VERSION 5.8 ;
BUSBITCHARS "[]" ;
DIVIDERCHAR "/" ;
UNITS
 DATABASE MICRONS 1000 ;
END UNITS
MANUFACTURINGGRID 0.001 ;
SITE GridSite
 CLASS CORE ;
 SYMMETRY X Y ;
 SIZE 0.450 BY 0.300 ;
END GridSite
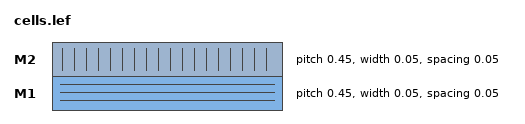
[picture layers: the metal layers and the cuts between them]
LAYER M1
 TYPE ROUTING ;
 DIRECTION HORIZONTAL ;
 PITCH 0.450 0.300 ;
 WIDTH 0.050 ;
 SPACING 0.050 ;
END M1
LAYER M2
 TYPE ROUTING ;
 DIRECTION VERTICAL ;
 PITCH 0.450 0.300 ;
 WIDTH 0.050 ;
 SPACING 0.050 ;
END M2
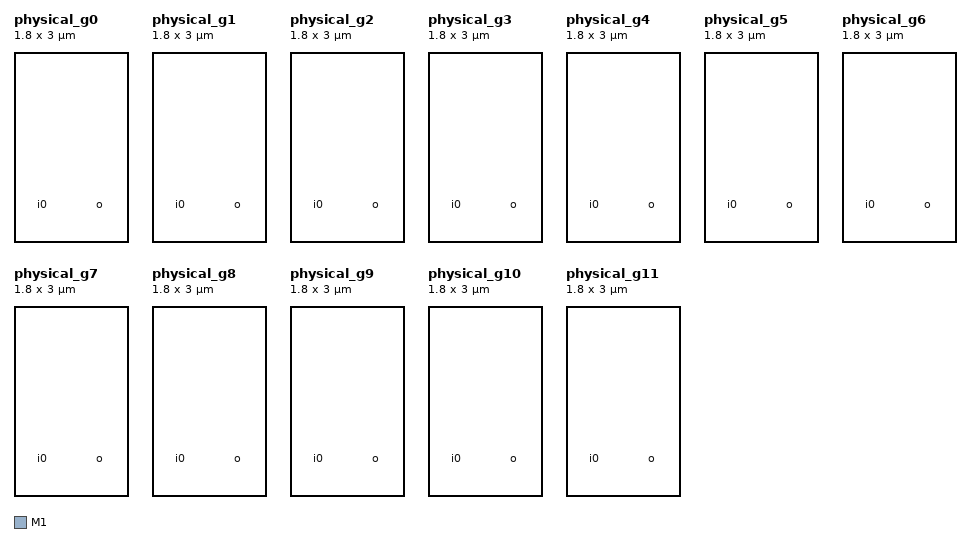
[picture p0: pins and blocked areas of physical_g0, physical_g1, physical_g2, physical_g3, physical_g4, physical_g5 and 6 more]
MACRO physical_g0
 CLASS CORE ;
 ORIGIN 0 0 ;
 SIZE 1.800000 BY 3.000000 ;
 SYMMETRY X Y ;
 SITE GridSite ;
 PIN i0
  DIRECTION INPUT ;
  USE SIGNAL ;
  PORT
   LAYER M1 ;
   RECT 0.440000 0.590000 0.460000 0.610000 ;
  END
 END i0
 PIN o
  DIRECTION OUTPUT ;
  USE SIGNAL ;
  PORT
   LAYER M1 ;
   RECT 1.340000 0.590000 1.360000 0.610000 ;
  END
 END o
END physical_g0
MACRO physical_g1
 CLASS CORE ;
 ORIGIN 0 0 ;
 SIZE 1.800000 BY 3.000000 ;
 SYMMETRY X Y ;
 SITE GridSite ;
 PIN i0
  DIRECTION INPUT ;
  USE SIGNAL ;
  PORT
   LAYER M1 ;
   RECT 0.440000 0.590000 0.460000 0.610000 ;
  END
 END i0
 PIN o
  DIRECTION OUTPUT ;
  USE SIGNAL ;
  PORT
   LAYER M1 ;
   RECT 1.340000 0.590000 1.360000 0.610000 ;
  END
 END o
END physical_g1
MACRO physical_g2
 CLASS CORE ;
 ORIGIN 0 0 ;
 SIZE 1.800000 BY 3.000000 ;
 SYMMETRY X Y ;
 SITE GridSite ;
 PIN i0
  DIRECTION INPUT ;
  USE SIGNAL ;
  PORT
   LAYER M1 ;
   RECT 0.440000 0.590000 0.460000 0.610000 ;
  END
 END i0
 PIN o
  DIRECTION OUTPUT ;
  USE SIGNAL ;
  PORT
   LAYER M1 ;
   RECT 1.340000 0.590000 1.360000 0.610000 ;
  END
 END o
END physical_g2
MACRO physical_g3
 CLASS CORE ;
 ORIGIN 0 0 ;
 SIZE 1.800000 BY 3.000000 ;
 SYMMETRY X Y ;
 SITE GridSite ;
 PIN i0
  DIRECTION INPUT ;
  USE SIGNAL ;
  PORT
   LAYER M1 ;
   RECT 0.440000 0.590000 0.460000 0.610000 ;
  END
 END i0
 PIN o
  DIRECTION OUTPUT ;
  USE SIGNAL ;
  PORT
   LAYER M1 ;
   RECT 1.340000 0.590000 1.360000 0.610000 ;
  END
 END o
END physical_g3
MACRO physical_g4
 CLASS CORE ;
 ORIGIN 0 0 ;
 SIZE 1.800000 BY 3.000000 ;
 SYMMETRY X Y ;
 SITE GridSite ;
 PIN i0
  DIRECTION INPUT ;
  USE SIGNAL ;
  PORT
   LAYER M1 ;
   RECT 0.440000 0.590000 0.460000 0.610000 ;
  END
 END i0
 PIN o
  DIRECTION OUTPUT ;
  USE SIGNAL ;
  PORT
   LAYER M1 ;
   RECT 1.340000 0.590000 1.360000 0.610000 ;
  END
 END o
END physical_g4
MACRO physical_g5
 CLASS CORE ;
 ORIGIN 0 0 ;
 SIZE 1.800000 BY 3.000000 ;
 SYMMETRY X Y ;
 SITE GridSite ;
 PIN i0
  DIRECTION INPUT ;
  USE SIGNAL ;
  PORT
   LAYER M1 ;
   RECT 0.440000 0.590000 0.460000 0.610000 ;
  END
 END i0
 PIN o
  DIRECTION OUTPUT ;
  USE SIGNAL ;
  PORT
   LAYER M1 ;
   RECT 1.340000 0.590000 1.360000 0.610000 ;
  END
 END o
END physical_g5
MACRO physical_g6
 CLASS CORE ;
 ORIGIN 0 0 ;
 SIZE 1.800000 BY 3.000000 ;
 SYMMETRY X Y ;
 SITE GridSite ;
 PIN i0
  DIRECTION INPUT ;
  USE SIGNAL ;
  PORT
   LAYER M1 ;
   RECT 0.440000 0.590000 0.460000 0.610000 ;
  END
 END i0
 PIN o
  DIRECTION OUTPUT ;
  USE SIGNAL ;
  PORT
   LAYER M1 ;
   RECT 1.340000 0.590000 1.360000 0.610000 ;
  END
 END o
END physical_g6
MACRO physical_g7
 CLASS CORE ;
 ORIGIN 0 0 ;
 SIZE 1.800000 BY 3.000000 ;
 SYMMETRY X Y ;
 SITE GridSite ;
 PIN i0
  DIRECTION INPUT ;
  USE SIGNAL ;
  PORT
   LAYER M1 ;
   RECT 0.440000 0.590000 0.460000 0.610000 ;
  END
 END i0
 PIN o
  DIRECTION OUTPUT ;
  USE SIGNAL ;
  PORT
   LAYER M1 ;
   RECT 1.340000 0.590000 1.360000 0.610000 ;
  END
 END o
END physical_g7
MACRO physical_g8
 CLASS CORE ;
 ORIGIN 0 0 ;
 SIZE 1.800000 BY 3.000000 ;
 SYMMETRY X Y ;
 SITE GridSite ;
 PIN i0
  DIRECTION INPUT ;
  USE SIGNAL ;
  PORT
   LAYER M1 ;
   RECT 0.440000 0.590000 0.460000 0.610000 ;
  END
 END i0
 PIN o
  DIRECTION OUTPUT ;
  USE SIGNAL ;
  PORT
   LAYER M1 ;
   RECT 1.340000 0.590000 1.360000 0.610000 ;
  END
 END o
END physical_g8
MACRO physical_g9
 CLASS CORE ;
 ORIGIN 0 0 ;
 SIZE 1.800000 BY 3.000000 ;
 SYMMETRY X Y ;
 SITE GridSite ;
 PIN i0
  DIRECTION INPUT ;
  USE SIGNAL ;
  PORT
   LAYER M1 ;
   RECT 0.440000 0.590000 0.460000 0.610000 ;
  END
 END i0
 PIN o
  DIRECTION OUTPUT ;
  USE SIGNAL ;
  PORT
   LAYER M1 ;
   RECT 1.340000 0.590000 1.360000 0.610000 ;
  END
 END o
END physical_g9
MACRO physical_g10
 CLASS CORE ;
 ORIGIN 0 0 ;
 SIZE 1.800000 BY 3.000000 ;
 SYMMETRY X Y ;
 SITE GridSite ;
 PIN i0
  DIRECTION INPUT ;
  USE SIGNAL ;
  PORT
   LAYER M1 ;
   RECT 0.440000 0.590000 0.460000 0.610000 ;
  END
 END i0
 PIN o
  DIRECTION OUTPUT ;
  USE SIGNAL ;
  PORT
   LAYER M1 ;
   RECT 1.340000 0.590000 1.360000 0.610000 ;
  END
 END o
END physical_g10
MACRO physical_g11
 CLASS CORE ;
 ORIGIN 0 0 ;
 SIZE 1.800000 BY 3.000000 ;
 SYMMETRY X Y ;
 SITE GridSite ;
 PIN i0
  DIRECTION INPUT ;
  USE SIGNAL ;
  PORT
   LAYER M1 ;
   RECT 0.440000 0.590000 0.460000 0.610000 ;
  END
 END i0
 PIN o
  DIRECTION OUTPUT ;
  USE SIGNAL ;
  PORT
   LAYER M1 ;
   RECT 1.340000 0.590000 1.360000 0.610000 ;
  END
 END o
END physical_g11
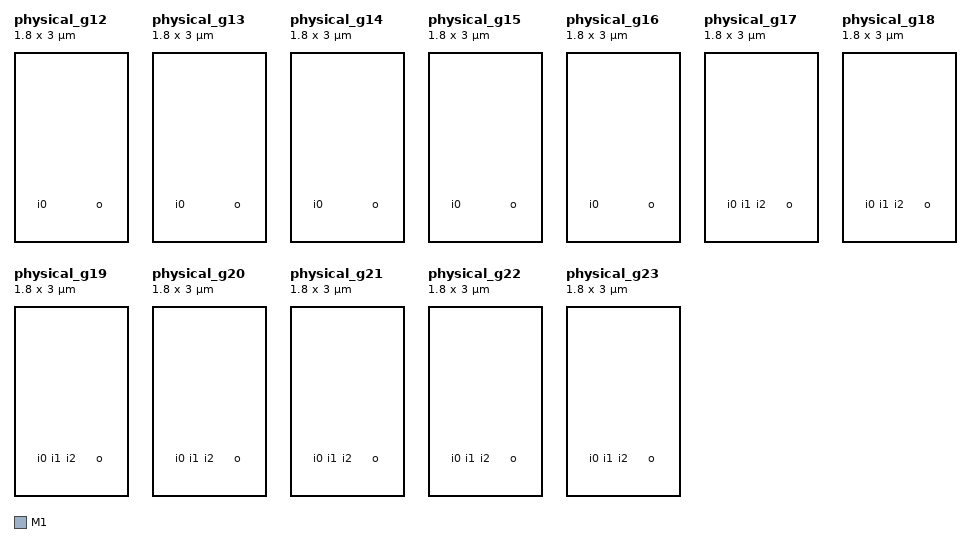
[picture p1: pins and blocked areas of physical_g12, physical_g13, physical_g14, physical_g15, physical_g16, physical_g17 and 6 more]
MACRO physical_g12
 CLASS CORE ;
 ORIGIN 0 0 ;
 SIZE 1.800000 BY 3.000000 ;
 SYMMETRY X Y ;
 SITE GridSite ;
 PIN i0
  DIRECTION INPUT ;
  USE SIGNAL ;
  PORT
   LAYER M1 ;
   RECT 0.440000 0.590000 0.460000 0.610000 ;
  END
 END i0
 PIN o
  DIRECTION OUTPUT ;
  USE SIGNAL ;
  PORT
   LAYER M1 ;
   RECT 1.340000 0.590000 1.360000 0.610000 ;
  END
 END o
END physical_g12
MACRO physical_g13
 CLASS CORE ;
 ORIGIN 0 0 ;
 SIZE 1.800000 BY 3.000000 ;
 SYMMETRY X Y ;
 SITE GridSite ;
 PIN i0
  DIRECTION INPUT ;
  USE SIGNAL ;
  PORT
   LAYER M1 ;
   RECT 0.440000 0.590000 0.460000 0.610000 ;
  END
 END i0
 PIN o
  DIRECTION OUTPUT ;
  USE SIGNAL ;
  PORT
   LAYER M1 ;
   RECT 1.340000 0.590000 1.360000 0.610000 ;
  END
 END o
END physical_g13
MACRO physical_g14
 CLASS CORE ;
 ORIGIN 0 0 ;
 SIZE 1.800000 BY 3.000000 ;
 SYMMETRY X Y ;
 SITE GridSite ;
 PIN i0
  DIRECTION INPUT ;
  USE SIGNAL ;
  PORT
   LAYER M1 ;
   RECT 0.440000 0.590000 0.460000 0.610000 ;
  END
 END i0
 PIN o
  DIRECTION OUTPUT ;
  USE SIGNAL ;
  PORT
   LAYER M1 ;
   RECT 1.340000 0.590000 1.360000 0.610000 ;
  END
 END o
END physical_g14
MACRO physical_g15
 CLASS CORE ;
 ORIGIN 0 0 ;
 SIZE 1.800000 BY 3.000000 ;
 SYMMETRY X Y ;
 SITE GridSite ;
 PIN i0
  DIRECTION INPUT ;
  USE SIGNAL ;
  PORT
   LAYER M1 ;
   RECT 0.440000 0.590000 0.460000 0.610000 ;
  END
 END i0
 PIN o
  DIRECTION OUTPUT ;
  USE SIGNAL ;
  PORT
   LAYER M1 ;
   RECT 1.340000 0.590000 1.360000 0.610000 ;
  END
 END o
END physical_g15
MACRO physical_g16
 CLASS CORE ;
 ORIGIN 0 0 ;
 SIZE 1.800000 BY 3.000000 ;
 SYMMETRY X Y ;
 SITE GridSite ;
 PIN i0
  DIRECTION INPUT ;
  USE SIGNAL ;
  PORT
   LAYER M1 ;
   RECT 0.440000 0.590000 0.460000 0.610000 ;
  END
 END i0
 PIN o
  DIRECTION OUTPUT ;
  USE SIGNAL ;
  PORT
   LAYER M1 ;
   RECT 1.340000 0.590000 1.360000 0.610000 ;
  END
 END o
END physical_g16
MACRO physical_g17
 CLASS CORE ;
 ORIGIN 0 0 ;
 SIZE 1.800000 BY 3.000000 ;
 SYMMETRY X Y ;
 SITE GridSite ;
 PIN i0
  DIRECTION INPUT ;
  USE SIGNAL ;
  PORT
   LAYER M1 ;
   RECT 0.440000 0.590000 0.460000 0.610000 ;
  END
 END i0
 PIN i1
  DIRECTION INPUT ;
  USE SIGNAL ;
  PORT
   LAYER M1 ;
   RECT 0.665000 0.590000 0.685000 0.610000 ;
  END
 END i1
 PIN i2
  DIRECTION INPUT ;
  USE SIGNAL ;
  PORT
   LAYER M1 ;
   RECT 0.890000 0.590000 0.910000 0.610000 ;
  END
 END i2
 PIN o
  DIRECTION OUTPUT ;
  USE SIGNAL ;
  PORT
   LAYER M1 ;
   RECT 1.340000 0.590000 1.360000 0.610000 ;
  END
 END o
END physical_g17
MACRO physical_g18
 CLASS CORE ;
 ORIGIN 0 0 ;
 SIZE 1.800000 BY 3.000000 ;
 SYMMETRY X Y ;
 SITE GridSite ;
 PIN i0
  DIRECTION INPUT ;
  USE SIGNAL ;
  PORT
   LAYER M1 ;
   RECT 0.440000 0.590000 0.460000 0.610000 ;
  END
 END i0
 PIN i1
  DIRECTION INPUT ;
  USE SIGNAL ;
  PORT
   LAYER M1 ;
   RECT 0.665000 0.590000 0.685000 0.610000 ;
  END
 END i1
 PIN i2
  DIRECTION INPUT ;
  USE SIGNAL ;
  PORT
   LAYER M1 ;
   RECT 0.890000 0.590000 0.910000 0.610000 ;
  END
 END i2
 PIN o
  DIRECTION OUTPUT ;
  USE SIGNAL ;
  PORT
   LAYER M1 ;
   RECT 1.340000 0.590000 1.360000 0.610000 ;
  END
 END o
END physical_g18
MACRO physical_g19
 CLASS CORE ;
 ORIGIN 0 0 ;
 SIZE 1.800000 BY 3.000000 ;
 SYMMETRY X Y ;
 SITE GridSite ;
 PIN i0
  DIRECTION INPUT ;
  USE SIGNAL ;
  PORT
   LAYER M1 ;
   RECT 0.440000 0.590000 0.460000 0.610000 ;
  END
 END i0
 PIN i1
  DIRECTION INPUT ;
  USE SIGNAL ;
  PORT
   LAYER M1 ;
   RECT 0.665000 0.590000 0.685000 0.610000 ;
  END
 END i1
 PIN i2
  DIRECTION INPUT ;
  USE SIGNAL ;
  PORT
   LAYER M1 ;
   RECT 0.890000 0.590000 0.910000 0.610000 ;
  END
 END i2
 PIN o
  DIRECTION OUTPUT ;
  USE SIGNAL ;
  PORT
   LAYER M1 ;
   RECT 1.340000 0.590000 1.360000 0.610000 ;
  END
 END o
END physical_g19
MACRO physical_g20
 CLASS CORE ;
 ORIGIN 0 0 ;
 SIZE 1.800000 BY 3.000000 ;
 SYMMETRY X Y ;
 SITE GridSite ;
 PIN i0
  DIRECTION INPUT ;
  USE SIGNAL ;
  PORT
   LAYER M1 ;
   RECT 0.440000 0.590000 0.460000 0.610000 ;
  END
 END i0
 PIN i1
  DIRECTION INPUT ;
  USE SIGNAL ;
  PORT
   LAYER M1 ;
   RECT 0.665000 0.590000 0.685000 0.610000 ;
  END
 END i1
 PIN i2
  DIRECTION INPUT ;
  USE SIGNAL ;
  PORT
   LAYER M1 ;
   RECT 0.890000 0.590000 0.910000 0.610000 ;
  END
 END i2
 PIN o
  DIRECTION OUTPUT ;
  USE SIGNAL ;
  PORT
   LAYER M1 ;
   RECT 1.340000 0.590000 1.360000 0.610000 ;
  END
 END o
END physical_g20
MACRO physical_g21
 CLASS CORE ;
 ORIGIN 0 0 ;
 SIZE 1.800000 BY 3.000000 ;
 SYMMETRY X Y ;
 SITE GridSite ;
 PIN i0
  DIRECTION INPUT ;
  USE SIGNAL ;
  PORT
   LAYER M1 ;
   RECT 0.440000 0.590000 0.460000 0.610000 ;
  END
 END i0
 PIN i1
  DIRECTION INPUT ;
  USE SIGNAL ;
  PORT
   LAYER M1 ;
   RECT 0.665000 0.590000 0.685000 0.610000 ;
  END
 END i1
 PIN i2
  DIRECTION INPUT ;
  USE SIGNAL ;
  PORT
   LAYER M1 ;
   RECT 0.890000 0.590000 0.910000 0.610000 ;
  END
 END i2
 PIN o
  DIRECTION OUTPUT ;
  USE SIGNAL ;
  PORT
   LAYER M1 ;
   RECT 1.340000 0.590000 1.360000 0.610000 ;
  END
 END o
END physical_g21
MACRO physical_g22
 CLASS CORE ;
 ORIGIN 0 0 ;
 SIZE 1.800000 BY 3.000000 ;
 SYMMETRY X Y ;
 SITE GridSite ;
 PIN i0
  DIRECTION INPUT ;
  USE SIGNAL ;
  PORT
   LAYER M1 ;
   RECT 0.440000 0.590000 0.460000 0.610000 ;
  END
 END i0
 PIN i1
  DIRECTION INPUT ;
  USE SIGNAL ;
  PORT
   LAYER M1 ;
   RECT 0.665000 0.590000 0.685000 0.610000 ;
  END
 END i1
 PIN i2
  DIRECTION INPUT ;
  USE SIGNAL ;
  PORT
   LAYER M1 ;
   RECT 0.890000 0.590000 0.910000 0.610000 ;
  END
 END i2
 PIN o
  DIRECTION OUTPUT ;
  USE SIGNAL ;
  PORT
   LAYER M1 ;
   RECT 1.340000 0.590000 1.360000 0.610000 ;
  END
 END o
END physical_g22
MACRO physical_g23
 CLASS CORE ;
 ORIGIN 0 0 ;
 SIZE 1.800000 BY 3.000000 ;
 SYMMETRY X Y ;
 SITE GridSite ;
 PIN i0
  DIRECTION INPUT ;
  USE SIGNAL ;
  PORT
   LAYER M1 ;
   RECT 0.440000 0.590000 0.460000 0.610000 ;
  END
 END i0
 PIN i1
  DIRECTION INPUT ;
  USE SIGNAL ;
  PORT
   LAYER M1 ;
   RECT 0.665000 0.590000 0.685000 0.610000 ;
  END
 END i1
 PIN i2
  DIRECTION INPUT ;
  USE SIGNAL ;
  PORT
   LAYER M1 ;
   RECT 0.890000 0.590000 0.910000 0.610000 ;
  END
 END i2
 PIN o
  DIRECTION OUTPUT ;
  USE SIGNAL ;
  PORT
   LAYER M1 ;
   RECT 1.340000 0.590000 1.360000 0.610000 ;
  END
 END o
END physical_g23
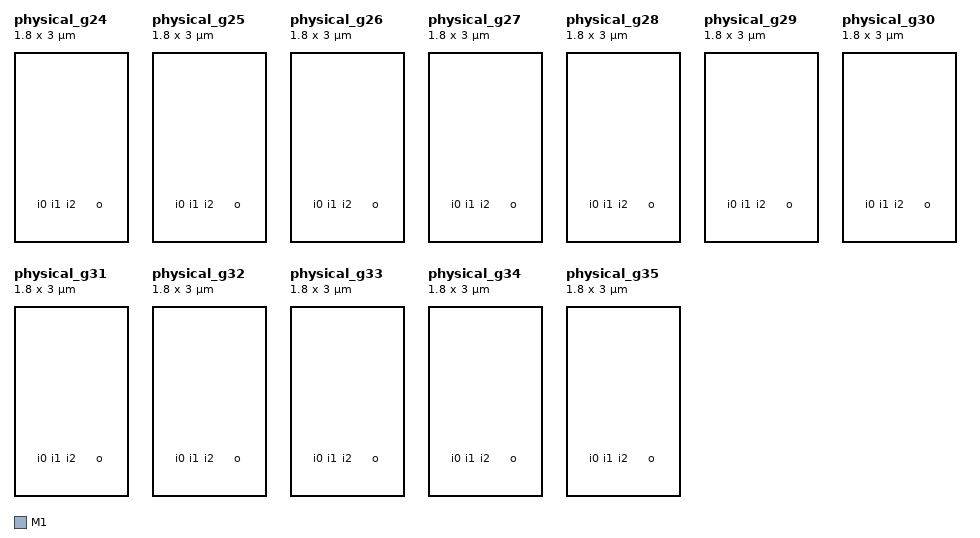
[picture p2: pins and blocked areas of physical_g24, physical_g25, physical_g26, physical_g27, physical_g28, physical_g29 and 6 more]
MACRO physical_g24
 CLASS CORE ;
 ORIGIN 0 0 ;
 SIZE 1.800000 BY 3.000000 ;
 SYMMETRY X Y ;
 SITE GridSite ;
 PIN i0
  DIRECTION INPUT ;
  USE SIGNAL ;
  PORT
   LAYER M1 ;
   RECT 0.440000 0.590000 0.460000 0.610000 ;
  END
 END i0
 PIN i1
  DIRECTION INPUT ;
  USE SIGNAL ;
  PORT
   LAYER M1 ;
   RECT 0.665000 0.590000 0.685000 0.610000 ;
  END
 END i1
 PIN i2
  DIRECTION INPUT ;
  USE SIGNAL ;
  PORT
   LAYER M1 ;
   RECT 0.890000 0.590000 0.910000 0.610000 ;
  END
 END i2
 PIN o
  DIRECTION OUTPUT ;
  USE SIGNAL ;
  PORT
   LAYER M1 ;
   RECT 1.340000 0.590000 1.360000 0.610000 ;
  END
 END o
END physical_g24
MACRO physical_g25
 CLASS CORE ;
 ORIGIN 0 0 ;
 SIZE 1.800000 BY 3.000000 ;
 SYMMETRY X Y ;
 SITE GridSite ;
 PIN i0
  DIRECTION INPUT ;
  USE SIGNAL ;
  PORT
   LAYER M1 ;
   RECT 0.440000 0.590000 0.460000 0.610000 ;
  END
 END i0
 PIN i1
  DIRECTION INPUT ;
  USE SIGNAL ;
  PORT
   LAYER M1 ;
   RECT 0.665000 0.590000 0.685000 0.610000 ;
  END
 END i1
 PIN i2
  DIRECTION INPUT ;
  USE SIGNAL ;
  PORT
   LAYER M1 ;
   RECT 0.890000 0.590000 0.910000 0.610000 ;
  END
 END i2
 PIN o
  DIRECTION OUTPUT ;
  USE SIGNAL ;
  PORT
   LAYER M1 ;
   RECT 1.340000 0.590000 1.360000 0.610000 ;
  END
 END o
END physical_g25
MACRO physical_g26
 CLASS CORE ;
 ORIGIN 0 0 ;
 SIZE 1.800000 BY 3.000000 ;
 SYMMETRY X Y ;
 SITE GridSite ;
 PIN i0
  DIRECTION INPUT ;
  USE SIGNAL ;
  PORT
   LAYER M1 ;
   RECT 0.440000 0.590000 0.460000 0.610000 ;
  END
 END i0
 PIN i1
  DIRECTION INPUT ;
  USE SIGNAL ;
  PORT
   LAYER M1 ;
   RECT 0.665000 0.590000 0.685000 0.610000 ;
  END
 END i1
 PIN i2
  DIRECTION INPUT ;
  USE SIGNAL ;
  PORT
   LAYER M1 ;
   RECT 0.890000 0.590000 0.910000 0.610000 ;
  END
 END i2
 PIN o
  DIRECTION OUTPUT ;
  USE SIGNAL ;
  PORT
   LAYER M1 ;
   RECT 1.340000 0.590000 1.360000 0.610000 ;
  END
 END o
END physical_g26
MACRO physical_g27
 CLASS CORE ;
 ORIGIN 0 0 ;
 SIZE 1.800000 BY 3.000000 ;
 SYMMETRY X Y ;
 SITE GridSite ;
 PIN i0
  DIRECTION INPUT ;
  USE SIGNAL ;
  PORT
   LAYER M1 ;
   RECT 0.440000 0.590000 0.460000 0.610000 ;
  END
 END i0
 PIN i1
  DIRECTION INPUT ;
  USE SIGNAL ;
  PORT
   LAYER M1 ;
   RECT 0.665000 0.590000 0.685000 0.610000 ;
  END
 END i1
 PIN i2
  DIRECTION INPUT ;
  USE SIGNAL ;
  PORT
   LAYER M1 ;
   RECT 0.890000 0.590000 0.910000 0.610000 ;
  END
 END i2
 PIN o
  DIRECTION OUTPUT ;
  USE SIGNAL ;
  PORT
   LAYER M1 ;
   RECT 1.340000 0.590000 1.360000 0.610000 ;
  END
 END o
END physical_g27
MACRO physical_g28
 CLASS CORE ;
 ORIGIN 0 0 ;
 SIZE 1.800000 BY 3.000000 ;
 SYMMETRY X Y ;
 SITE GridSite ;
 PIN i0
  DIRECTION INPUT ;
  USE SIGNAL ;
  PORT
   LAYER M1 ;
   RECT 0.440000 0.590000 0.460000 0.610000 ;
  END
 END i0
 PIN i1
  DIRECTION INPUT ;
  USE SIGNAL ;
  PORT
   LAYER M1 ;
   RECT 0.665000 0.590000 0.685000 0.610000 ;
  END
 END i1
 PIN i2
  DIRECTION INPUT ;
  USE SIGNAL ;
  PORT
   LAYER M1 ;
   RECT 0.890000 0.590000 0.910000 0.610000 ;
  END
 END i2
 PIN o
  DIRECTION OUTPUT ;
  USE SIGNAL ;
  PORT
   LAYER M1 ;
   RECT 1.340000 0.590000 1.360000 0.610000 ;
  END
 END o
END physical_g28
MACRO physical_g29
 CLASS CORE ;
 ORIGIN 0 0 ;
 SIZE 1.800000 BY 3.000000 ;
 SYMMETRY X Y ;
 SITE GridSite ;
 PIN i0
  DIRECTION INPUT ;
  USE SIGNAL ;
  PORT
   LAYER M1 ;
   RECT 0.440000 0.590000 0.460000 0.610000 ;
  END
 END i0
 PIN i1
  DIRECTION INPUT ;
  USE SIGNAL ;
  PORT
   LAYER M1 ;
   RECT 0.665000 0.590000 0.685000 0.610000 ;
  END
 END i1
 PIN i2
  DIRECTION INPUT ;
  USE SIGNAL ;
  PORT
   LAYER M1 ;
   RECT 0.890000 0.590000 0.910000 0.610000 ;
  END
 END i2
 PIN o
  DIRECTION OUTPUT ;
  USE SIGNAL ;
  PORT
   LAYER M1 ;
   RECT 1.340000 0.590000 1.360000 0.610000 ;
  END
 END o
END physical_g29
MACRO physical_g30
 CLASS CORE ;
 ORIGIN 0 0 ;
 SIZE 1.800000 BY 3.000000 ;
 SYMMETRY X Y ;
 SITE GridSite ;
 PIN i0
  DIRECTION INPUT ;
  USE SIGNAL ;
  PORT
   LAYER M1 ;
   RECT 0.440000 0.590000 0.460000 0.610000 ;
  END
 END i0
 PIN i1
  DIRECTION INPUT ;
  USE SIGNAL ;
  PORT
   LAYER M1 ;
   RECT 0.665000 0.590000 0.685000 0.610000 ;
  END
 END i1
 PIN i2
  DIRECTION INPUT ;
  USE SIGNAL ;
  PORT
   LAYER M1 ;
   RECT 0.890000 0.590000 0.910000 0.610000 ;
  END
 END i2
 PIN o
  DIRECTION OUTPUT ;
  USE SIGNAL ;
  PORT
   LAYER M1 ;
   RECT 1.340000 0.590000 1.360000 0.610000 ;
  END
 END o
END physical_g30
MACRO physical_g31
 CLASS CORE ;
 ORIGIN 0 0 ;
 SIZE 1.800000 BY 3.000000 ;
 SYMMETRY X Y ;
 SITE GridSite ;
 PIN i0
  DIRECTION INPUT ;
  USE SIGNAL ;
  PORT
   LAYER M1 ;
   RECT 0.440000 0.590000 0.460000 0.610000 ;
  END
 END i0
 PIN i1
  DIRECTION INPUT ;
  USE SIGNAL ;
  PORT
   LAYER M1 ;
   RECT 0.665000 0.590000 0.685000 0.610000 ;
  END
 END i1
 PIN i2
  DIRECTION INPUT ;
  USE SIGNAL ;
  PORT
   LAYER M1 ;
   RECT 0.890000 0.590000 0.910000 0.610000 ;
  END
 END i2
 PIN o
  DIRECTION OUTPUT ;
  USE SIGNAL ;
  PORT
   LAYER M1 ;
   RECT 1.340000 0.590000 1.360000 0.610000 ;
  END
 END o
END physical_g31
MACRO physical_g32
 CLASS CORE ;
 ORIGIN 0 0 ;
 SIZE 1.800000 BY 3.000000 ;
 SYMMETRY X Y ;
 SITE GridSite ;
 PIN i0
  DIRECTION INPUT ;
  USE SIGNAL ;
  PORT
   LAYER M1 ;
   RECT 0.440000 0.590000 0.460000 0.610000 ;
  END
 END i0
 PIN i1
  DIRECTION INPUT ;
  USE SIGNAL ;
  PORT
   LAYER M1 ;
   RECT 0.665000 0.590000 0.685000 0.610000 ;
  END
 END i1
 PIN i2
  DIRECTION INPUT ;
  USE SIGNAL ;
  PORT
   LAYER M1 ;
   RECT 0.890000 0.590000 0.910000 0.610000 ;
  END
 END i2
 PIN o
  DIRECTION OUTPUT ;
  USE SIGNAL ;
  PORT
   LAYER M1 ;
   RECT 1.340000 0.590000 1.360000 0.610000 ;
  END
 END o
END physical_g32
MACRO physical_g33
 CLASS CORE ;
 ORIGIN 0 0 ;
 SIZE 1.800000 BY 3.000000 ;
 SYMMETRY X Y ;
 SITE GridSite ;
 PIN i0
  DIRECTION INPUT ;
  USE SIGNAL ;
  PORT
   LAYER M1 ;
   RECT 0.440000 0.590000 0.460000 0.610000 ;
  END
 END i0
 PIN i1
  DIRECTION INPUT ;
  USE SIGNAL ;
  PORT
   LAYER M1 ;
   RECT 0.665000 0.590000 0.685000 0.610000 ;
  END
 END i1
 PIN i2
  DIRECTION INPUT ;
  USE SIGNAL ;
  PORT
   LAYER M1 ;
   RECT 0.890000 0.590000 0.910000 0.610000 ;
  END
 END i2
 PIN o
  DIRECTION OUTPUT ;
  USE SIGNAL ;
  PORT
   LAYER M1 ;
   RECT 1.340000 0.590000 1.360000 0.610000 ;
  END
 END o
END physical_g33
MACRO physical_g34
 CLASS CORE ;
 ORIGIN 0 0 ;
 SIZE 1.800000 BY 3.000000 ;
 SYMMETRY X Y ;
 SITE GridSite ;
 PIN i0
  DIRECTION INPUT ;
  USE SIGNAL ;
  PORT
   LAYER M1 ;
   RECT 0.440000 0.590000 0.460000 0.610000 ;
  END
 END i0
 PIN i1
  DIRECTION INPUT ;
  USE SIGNAL ;
  PORT
   LAYER M1 ;
   RECT 0.665000 0.590000 0.685000 0.610000 ;
  END
 END i1
 PIN i2
  DIRECTION INPUT ;
  USE SIGNAL ;
  PORT
   LAYER M1 ;
   RECT 0.890000 0.590000 0.910000 0.610000 ;
  END
 END i2
 PIN o
  DIRECTION OUTPUT ;
  USE SIGNAL ;
  PORT
   LAYER M1 ;
   RECT 1.340000 0.590000 1.360000 0.610000 ;
  END
 END o
END physical_g34
MACRO physical_g35
 CLASS CORE ;
 ORIGIN 0 0 ;
 SIZE 1.800000 BY 3.000000 ;
 SYMMETRY X Y ;
 SITE GridSite ;
 PIN i0
  DIRECTION INPUT ;
  USE SIGNAL ;
  PORT
   LAYER M1 ;
   RECT 0.440000 0.590000 0.460000 0.610000 ;
  END
 END i0
 PIN i1
  DIRECTION INPUT ;
  USE SIGNAL ;
  PORT
   LAYER M1 ;
   RECT 0.665000 0.590000 0.685000 0.610000 ;
  END
 END i1
 PIN i2
  DIRECTION INPUT ;
  USE SIGNAL ;
  PORT
   LAYER M1 ;
   RECT 0.890000 0.590000 0.910000 0.610000 ;
  END
 END i2
 PIN o
  DIRECTION OUTPUT ;
  USE SIGNAL ;
  PORT
   LAYER M1 ;
   RECT 1.340000 0.590000 1.360000 0.610000 ;
  END
 END o
END physical_g35
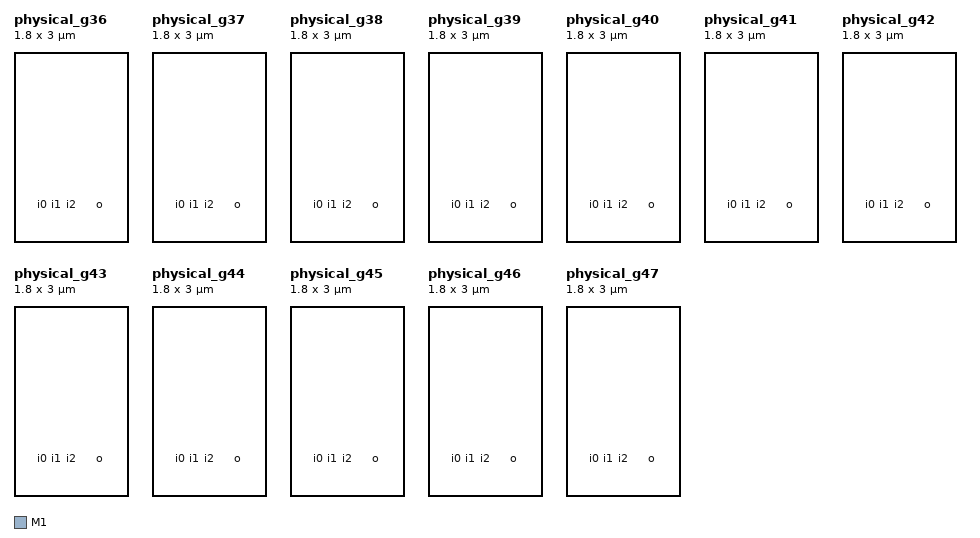
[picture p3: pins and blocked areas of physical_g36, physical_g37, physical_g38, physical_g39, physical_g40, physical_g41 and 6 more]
MACRO physical_g36
 CLASS CORE ;
 ORIGIN 0 0 ;
 SIZE 1.800000 BY 3.000000 ;
 SYMMETRY X Y ;
 SITE GridSite ;
 PIN i0
  DIRECTION INPUT ;
  USE SIGNAL ;
  PORT
   LAYER M1 ;
   RECT 0.440000 0.590000 0.460000 0.610000 ;
  END
 END i0
 PIN i1
  DIRECTION INPUT ;
  USE SIGNAL ;
  PORT
   LAYER M1 ;
   RECT 0.665000 0.590000 0.685000 0.610000 ;
  END
 END i1
 PIN i2
  DIRECTION INPUT ;
  USE SIGNAL ;
  PORT
   LAYER M1 ;
   RECT 0.890000 0.590000 0.910000 0.610000 ;
  END
 END i2
 PIN o
  DIRECTION OUTPUT ;
  USE SIGNAL ;
  PORT
   LAYER M1 ;
   RECT 1.340000 0.590000 1.360000 0.610000 ;
  END
 END o
END physical_g36
MACRO physical_g37
 CLASS CORE ;
 ORIGIN 0 0 ;
 SIZE 1.800000 BY 3.000000 ;
 SYMMETRY X Y ;
 SITE GridSite ;
 PIN i0
  DIRECTION INPUT ;
  USE SIGNAL ;
  PORT
   LAYER M1 ;
   RECT 0.440000 0.590000 0.460000 0.610000 ;
  END
 END i0
 PIN i1
  DIRECTION INPUT ;
  USE SIGNAL ;
  PORT
   LAYER M1 ;
   RECT 0.665000 0.590000 0.685000 0.610000 ;
  END
 END i1
 PIN i2
  DIRECTION INPUT ;
  USE SIGNAL ;
  PORT
   LAYER M1 ;
   RECT 0.890000 0.590000 0.910000 0.610000 ;
  END
 END i2
 PIN o
  DIRECTION OUTPUT ;
  USE SIGNAL ;
  PORT
   LAYER M1 ;
   RECT 1.340000 0.590000 1.360000 0.610000 ;
  END
 END o
END physical_g37
MACRO physical_g38
 CLASS CORE ;
 ORIGIN 0 0 ;
 SIZE 1.800000 BY 3.000000 ;
 SYMMETRY X Y ;
 SITE GridSite ;
 PIN i0
  DIRECTION INPUT ;
  USE SIGNAL ;
  PORT
   LAYER M1 ;
   RECT 0.440000 0.590000 0.460000 0.610000 ;
  END
 END i0
 PIN i1
  DIRECTION INPUT ;
  USE SIGNAL ;
  PORT
   LAYER M1 ;
   RECT 0.665000 0.590000 0.685000 0.610000 ;
  END
 END i1
 PIN i2
  DIRECTION INPUT ;
  USE SIGNAL ;
  PORT
   LAYER M1 ;
   RECT 0.890000 0.590000 0.910000 0.610000 ;
  END
 END i2
 PIN o
  DIRECTION OUTPUT ;
  USE SIGNAL ;
  PORT
   LAYER M1 ;
   RECT 1.340000 0.590000 1.360000 0.610000 ;
  END
 END o
END physical_g38
MACRO physical_g39
 CLASS CORE ;
 ORIGIN 0 0 ;
 SIZE 1.800000 BY 3.000000 ;
 SYMMETRY X Y ;
 SITE GridSite ;
 PIN i0
  DIRECTION INPUT ;
  USE SIGNAL ;
  PORT
   LAYER M1 ;
   RECT 0.440000 0.590000 0.460000 0.610000 ;
  END
 END i0
 PIN i1
  DIRECTION INPUT ;
  USE SIGNAL ;
  PORT
   LAYER M1 ;
   RECT 0.665000 0.590000 0.685000 0.610000 ;
  END
 END i1
 PIN i2
  DIRECTION INPUT ;
  USE SIGNAL ;
  PORT
   LAYER M1 ;
   RECT 0.890000 0.590000 0.910000 0.610000 ;
  END
 END i2
 PIN o
  DIRECTION OUTPUT ;
  USE SIGNAL ;
  PORT
   LAYER M1 ;
   RECT 1.340000 0.590000 1.360000 0.610000 ;
  END
 END o
END physical_g39
MACRO physical_g40
 CLASS CORE ;
 ORIGIN 0 0 ;
 SIZE 1.800000 BY 3.000000 ;
 SYMMETRY X Y ;
 SITE GridSite ;
 PIN i0
  DIRECTION INPUT ;
  USE SIGNAL ;
  PORT
   LAYER M1 ;
   RECT 0.440000 0.590000 0.460000 0.610000 ;
  END
 END i0
 PIN i1
  DIRECTION INPUT ;
  USE SIGNAL ;
  PORT
   LAYER M1 ;
   RECT 0.665000 0.590000 0.685000 0.610000 ;
  END
 END i1
 PIN i2
  DIRECTION INPUT ;
  USE SIGNAL ;
  PORT
   LAYER M1 ;
   RECT 0.890000 0.590000 0.910000 0.610000 ;
  END
 END i2
 PIN o
  DIRECTION OUTPUT ;
  USE SIGNAL ;
  PORT
   LAYER M1 ;
   RECT 1.340000 0.590000 1.360000 0.610000 ;
  END
 END o
END physical_g40
MACRO physical_g41
 CLASS CORE ;
 ORIGIN 0 0 ;
 SIZE 1.800000 BY 3.000000 ;
 SYMMETRY X Y ;
 SITE GridSite ;
 PIN i0
  DIRECTION INPUT ;
  USE SIGNAL ;
  PORT
   LAYER M1 ;
   RECT 0.440000 0.590000 0.460000 0.610000 ;
  END
 END i0
 PIN i1
  DIRECTION INPUT ;
  USE SIGNAL ;
  PORT
   LAYER M1 ;
   RECT 0.665000 0.590000 0.685000 0.610000 ;
  END
 END i1
 PIN i2
  DIRECTION INPUT ;
  USE SIGNAL ;
  PORT
   LAYER M1 ;
   RECT 0.890000 0.590000 0.910000 0.610000 ;
  END
 END i2
 PIN o
  DIRECTION OUTPUT ;
  USE SIGNAL ;
  PORT
   LAYER M1 ;
   RECT 1.340000 0.590000 1.360000 0.610000 ;
  END
 END o
END physical_g41
MACRO physical_g42
 CLASS CORE ;
 ORIGIN 0 0 ;
 SIZE 1.800000 BY 3.000000 ;
 SYMMETRY X Y ;
 SITE GridSite ;
 PIN i0
  DIRECTION INPUT ;
  USE SIGNAL ;
  PORT
   LAYER M1 ;
   RECT 0.440000 0.590000 0.460000 0.610000 ;
  END
 END i0
 PIN i1
  DIRECTION INPUT ;
  USE SIGNAL ;
  PORT
   LAYER M1 ;
   RECT 0.665000 0.590000 0.685000 0.610000 ;
  END
 END i1
 PIN i2
  DIRECTION INPUT ;
  USE SIGNAL ;
  PORT
   LAYER M1 ;
   RECT 0.890000 0.590000 0.910000 0.610000 ;
  END
 END i2
 PIN o
  DIRECTION OUTPUT ;
  USE SIGNAL ;
  PORT
   LAYER M1 ;
   RECT 1.340000 0.590000 1.360000 0.610000 ;
  END
 END o
END physical_g42
MACRO physical_g43
 CLASS CORE ;
 ORIGIN 0 0 ;
 SIZE 1.800000 BY 3.000000 ;
 SYMMETRY X Y ;
 SITE GridSite ;
 PIN i0
  DIRECTION INPUT ;
  USE SIGNAL ;
  PORT
   LAYER M1 ;
   RECT 0.440000 0.590000 0.460000 0.610000 ;
  END
 END i0
 PIN i1
  DIRECTION INPUT ;
  USE SIGNAL ;
  PORT
   LAYER M1 ;
   RECT 0.665000 0.590000 0.685000 0.610000 ;
  END
 END i1
 PIN i2
  DIRECTION INPUT ;
  USE SIGNAL ;
  PORT
   LAYER M1 ;
   RECT 0.890000 0.590000 0.910000 0.610000 ;
  END
 END i2
 PIN o
  DIRECTION OUTPUT ;
  USE SIGNAL ;
  PORT
   LAYER M1 ;
   RECT 1.340000 0.590000 1.360000 0.610000 ;
  END
 END o
END physical_g43
MACRO physical_g44
 CLASS CORE ;
 ORIGIN 0 0 ;
 SIZE 1.800000 BY 3.000000 ;
 SYMMETRY X Y ;
 SITE GridSite ;
 PIN i0
  DIRECTION INPUT ;
  USE SIGNAL ;
  PORT
   LAYER M1 ;
   RECT 0.440000 0.590000 0.460000 0.610000 ;
  END
 END i0
 PIN i1
  DIRECTION INPUT ;
  USE SIGNAL ;
  PORT
   LAYER M1 ;
   RECT 0.665000 0.590000 0.685000 0.610000 ;
  END
 END i1
 PIN i2
  DIRECTION INPUT ;
  USE SIGNAL ;
  PORT
   LAYER M1 ;
   RECT 0.890000 0.590000 0.910000 0.610000 ;
  END
 END i2
 PIN o
  DIRECTION OUTPUT ;
  USE SIGNAL ;
  PORT
   LAYER M1 ;
   RECT 1.340000 0.590000 1.360000 0.610000 ;
  END
 END o
END physical_g44
MACRO physical_g45
 CLASS CORE ;
 ORIGIN 0 0 ;
 SIZE 1.800000 BY 3.000000 ;
 SYMMETRY X Y ;
 SITE GridSite ;
 PIN i0
  DIRECTION INPUT ;
  USE SIGNAL ;
  PORT
   LAYER M1 ;
   RECT 0.440000 0.590000 0.460000 0.610000 ;
  END
 END i0
 PIN i1
  DIRECTION INPUT ;
  USE SIGNAL ;
  PORT
   LAYER M1 ;
   RECT 0.665000 0.590000 0.685000 0.610000 ;
  END
 END i1
 PIN i2
  DIRECTION INPUT ;
  USE SIGNAL ;
  PORT
   LAYER M1 ;
   RECT 0.890000 0.590000 0.910000 0.610000 ;
  END
 END i2
 PIN o
  DIRECTION OUTPUT ;
  USE SIGNAL ;
  PORT
   LAYER M1 ;
   RECT 1.340000 0.590000 1.360000 0.610000 ;
  END
 END o
END physical_g45
MACRO physical_g46
 CLASS CORE ;
 ORIGIN 0 0 ;
 SIZE 1.800000 BY 3.000000 ;
 SYMMETRY X Y ;
 SITE GridSite ;
 PIN i0
  DIRECTION INPUT ;
  USE SIGNAL ;
  PORT
   LAYER M1 ;
   RECT 0.440000 0.590000 0.460000 0.610000 ;
  END
 END i0
 PIN i1
  DIRECTION INPUT ;
  USE SIGNAL ;
  PORT
   LAYER M1 ;
   RECT 0.665000 0.590000 0.685000 0.610000 ;
  END
 END i1
 PIN i2
  DIRECTION INPUT ;
  USE SIGNAL ;
  PORT
   LAYER M1 ;
   RECT 0.890000 0.590000 0.910000 0.610000 ;
  END
 END i2
 PIN o
  DIRECTION OUTPUT ;
  USE SIGNAL ;
  PORT
   LAYER M1 ;
   RECT 1.340000 0.590000 1.360000 0.610000 ;
  END
 END o
END physical_g46
MACRO physical_g47
 CLASS CORE ;
 ORIGIN 0 0 ;
 SIZE 1.800000 BY 3.000000 ;
 SYMMETRY X Y ;
 SITE GridSite ;
 PIN i0
  DIRECTION INPUT ;
  USE SIGNAL ;
  PORT
   LAYER M1 ;
   RECT 0.440000 0.590000 0.460000 0.610000 ;
  END
 END i0
 PIN i1
  DIRECTION INPUT ;
  USE SIGNAL ;
  PORT
   LAYER M1 ;
   RECT 0.665000 0.590000 0.685000 0.610000 ;
  END
 END i1
 PIN i2
  DIRECTION INPUT ;
  USE SIGNAL ;
  PORT
   LAYER M1 ;
   RECT 0.890000 0.590000 0.910000 0.610000 ;
  END
 END i2
 PIN o
  DIRECTION OUTPUT ;
  USE SIGNAL ;
  PORT
   LAYER M1 ;
   RECT 1.340000 0.590000 1.360000 0.610000 ;
  END
 END o
END physical_g47
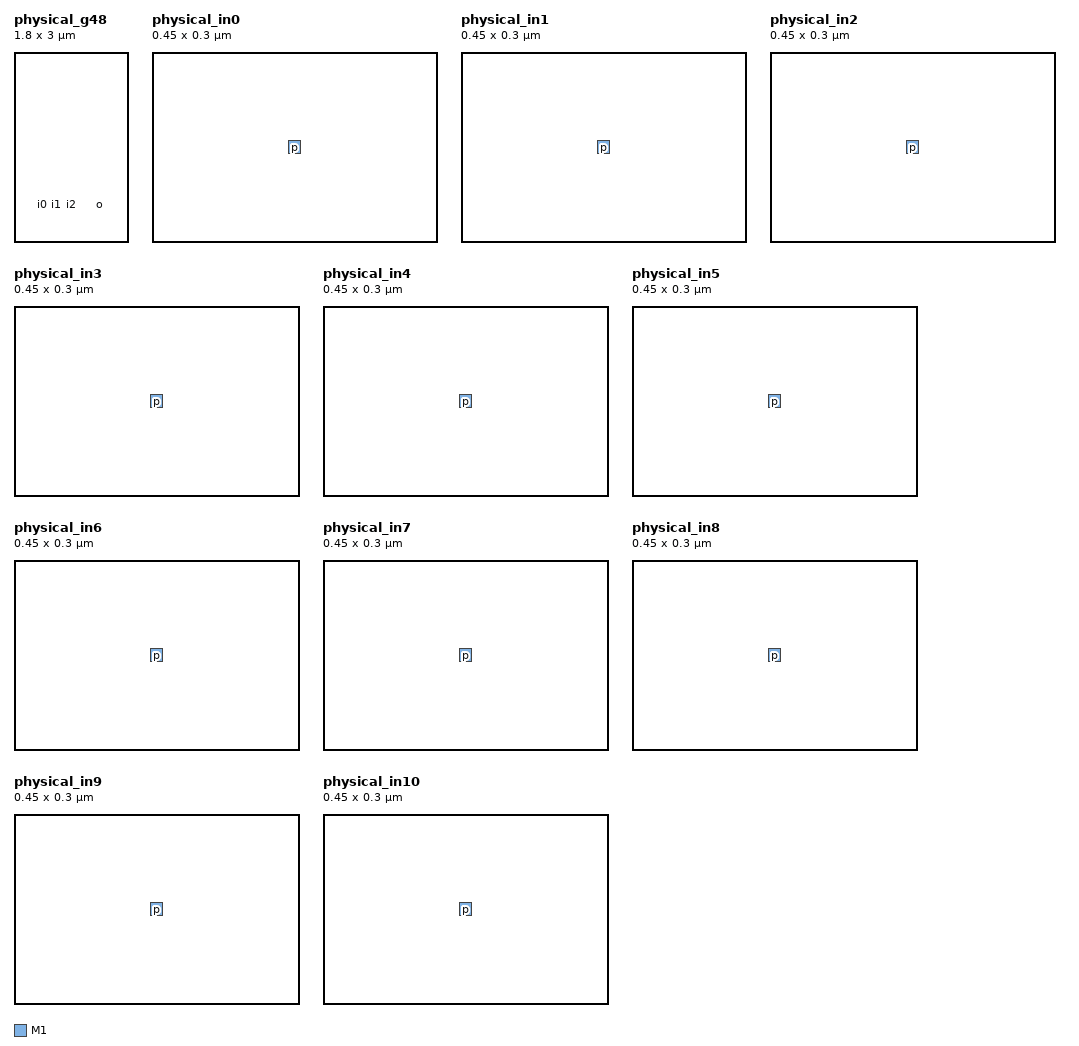
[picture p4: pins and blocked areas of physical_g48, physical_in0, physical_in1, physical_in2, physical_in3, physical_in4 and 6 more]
MACRO physical_g48
 CLASS CORE ;
 ORIGIN 0 0 ;
 SIZE 1.800000 BY 3.000000 ;
 SYMMETRY X Y ;
 SITE GridSite ;
 PIN i0
  DIRECTION INPUT ;
  USE SIGNAL ;
  PORT
   LAYER M1 ;
   RECT 0.440000 0.590000 0.460000 0.610000 ;
  END
 END i0
 PIN i1
  DIRECTION INPUT ;
  USE SIGNAL ;
  PORT
   LAYER M1 ;
   RECT 0.665000 0.590000 0.685000 0.610000 ;
  END
 END i1
 PIN i2
  DIRECTION INPUT ;
  USE SIGNAL ;
  PORT
   LAYER M1 ;
   RECT 0.890000 0.590000 0.910000 0.610000 ;
  END
 END i2
 PIN o
  DIRECTION OUTPUT ;
  USE SIGNAL ;
  PORT
   LAYER M1 ;
   RECT 1.340000 0.590000 1.360000 0.610000 ;
  END
 END o
END physical_g48
MACRO physical_in0
 CLASS CORE ;
 ORIGIN 0 0 ;
 SIZE 0.450000 BY 0.300000 ;
 SYMMETRY X Y ;
 SITE GridSite ;
 PIN p
  DIRECTION INPUT ;
  USE SIGNAL ;
  PORT
   LAYER M1 ;
   RECT 0.215000 0.140000 0.235000 0.160000 ;
  END
 END p
END physical_in0
MACRO physical_in1
 CLASS CORE ;
 ORIGIN 0 0 ;
 SIZE 0.450000 BY 0.300000 ;
 SYMMETRY X Y ;
 SITE GridSite ;
 PIN p
  DIRECTION INPUT ;
  USE SIGNAL ;
  PORT
   LAYER M1 ;
   RECT 0.215000 0.140000 0.235000 0.160000 ;
  END
 END p
END physical_in1
MACRO physical_in2
 CLASS CORE ;
 ORIGIN 0 0 ;
 SIZE 0.450000 BY 0.300000 ;
 SYMMETRY X Y ;
 SITE GridSite ;
 PIN p
  DIRECTION INPUT ;
  USE SIGNAL ;
  PORT
   LAYER M1 ;
   RECT 0.215000 0.140000 0.235000 0.160000 ;
  END
 END p
END physical_in2
MACRO physical_in3
 CLASS CORE ;
 ORIGIN 0 0 ;
 SIZE 0.450000 BY 0.300000 ;
 SYMMETRY X Y ;
 SITE GridSite ;
 PIN p
  DIRECTION INPUT ;
  USE SIGNAL ;
  PORT
   LAYER M1 ;
   RECT 0.215000 0.140000 0.235000 0.160000 ;
  END
 END p
END physical_in3
MACRO physical_in4
 CLASS CORE ;
 ORIGIN 0 0 ;
 SIZE 0.450000 BY 0.300000 ;
 SYMMETRY X Y ;
 SITE GridSite ;
 PIN p
  DIRECTION INPUT ;
  USE SIGNAL ;
  PORT
   LAYER M1 ;
   RECT 0.215000 0.140000 0.235000 0.160000 ;
  END
 END p
END physical_in4
MACRO physical_in5
 CLASS CORE ;
 ORIGIN 0 0 ;
 SIZE 0.450000 BY 0.300000 ;
 SYMMETRY X Y ;
 SITE GridSite ;
 PIN p
  DIRECTION INPUT ;
  USE SIGNAL ;
  PORT
   LAYER M1 ;
   RECT 0.215000 0.140000 0.235000 0.160000 ;
  END
 END p
END physical_in5
MACRO physical_in6
 CLASS CORE ;
 ORIGIN 0 0 ;
 SIZE 0.450000 BY 0.300000 ;
 SYMMETRY X Y ;
 SITE GridSite ;
 PIN p
  DIRECTION INPUT ;
  USE SIGNAL ;
  PORT
   LAYER M1 ;
   RECT 0.215000 0.140000 0.235000 0.160000 ;
  END
 END p
END physical_in6
MACRO physical_in7
 CLASS CORE ;
 ORIGIN 0 0 ;
 SIZE 0.450000 BY 0.300000 ;
 SYMMETRY X Y ;
 SITE GridSite ;
 PIN p
  DIRECTION INPUT ;
  USE SIGNAL ;
  PORT
   LAYER M1 ;
   RECT 0.215000 0.140000 0.235000 0.160000 ;
  END
 END p
END physical_in7
MACRO physical_in8
 CLASS CORE ;
 ORIGIN 0 0 ;
 SIZE 0.450000 BY 0.300000 ;
 SYMMETRY X Y ;
 SITE GridSite ;
 PIN p
  DIRECTION INPUT ;
  USE SIGNAL ;
  PORT
   LAYER M1 ;
   RECT 0.215000 0.140000 0.235000 0.160000 ;
  END
 END p
END physical_in8
MACRO physical_in9
 CLASS CORE ;
 ORIGIN 0 0 ;
 SIZE 0.450000 BY 0.300000 ;
 SYMMETRY X Y ;
 SITE GridSite ;
 PIN p
  DIRECTION INPUT ;
  USE SIGNAL ;
  PORT
   LAYER M1 ;
   RECT 0.215000 0.140000 0.235000 0.160000 ;
  END
 END p
END physical_in9
MACRO physical_in10
 CLASS CORE ;
 ORIGIN 0 0 ;
 SIZE 0.450000 BY 0.300000 ;
 SYMMETRY X Y ;
 SITE GridSite ;
 PIN p
  DIRECTION INPUT ;
  USE SIGNAL ;
  PORT
   LAYER M1 ;
   RECT 0.215000 0.140000 0.235000 0.160000 ;
  END
 END p
END physical_in10
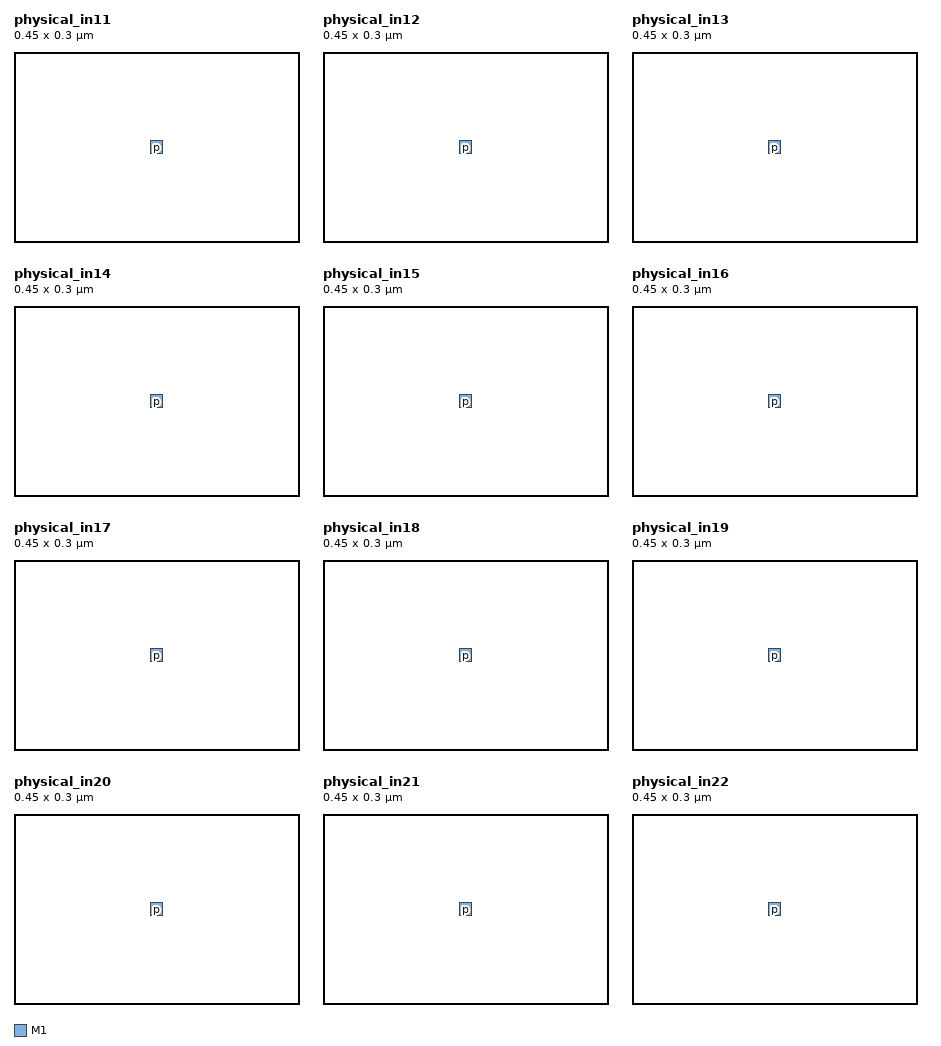
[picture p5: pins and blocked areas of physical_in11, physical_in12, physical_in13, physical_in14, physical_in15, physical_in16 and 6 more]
MACRO physical_in11
 CLASS CORE ;
 ORIGIN 0 0 ;
 SIZE 0.450000 BY 0.300000 ;
 SYMMETRY X Y ;
 SITE GridSite ;
 PIN p
  DIRECTION INPUT ;
  USE SIGNAL ;
  PORT
   LAYER M1 ;
   RECT 0.215000 0.140000 0.235000 0.160000 ;
  END
 END p
END physical_in11
MACRO physical_in12
 CLASS CORE ;
 ORIGIN 0 0 ;
 SIZE 0.450000 BY 0.300000 ;
 SYMMETRY X Y ;
 SITE GridSite ;
 PIN p
  DIRECTION INPUT ;
  USE SIGNAL ;
  PORT
   LAYER M1 ;
   RECT 0.215000 0.140000 0.235000 0.160000 ;
  END
 END p
END physical_in12
MACRO physical_in13
 CLASS CORE ;
 ORIGIN 0 0 ;
 SIZE 0.450000 BY 0.300000 ;
 SYMMETRY X Y ;
 SITE GridSite ;
 PIN p
  DIRECTION INPUT ;
  USE SIGNAL ;
  PORT
   LAYER M1 ;
   RECT 0.215000 0.140000 0.235000 0.160000 ;
  END
 END p
END physical_in13
MACRO physical_in14
 CLASS CORE ;
 ORIGIN 0 0 ;
 SIZE 0.450000 BY 0.300000 ;
 SYMMETRY X Y ;
 SITE GridSite ;
 PIN p
  DIRECTION INPUT ;
  USE SIGNAL ;
  PORT
   LAYER M1 ;
   RECT 0.215000 0.140000 0.235000 0.160000 ;
  END
 END p
END physical_in14
MACRO physical_in15
 CLASS CORE ;
 ORIGIN 0 0 ;
 SIZE 0.450000 BY 0.300000 ;
 SYMMETRY X Y ;
 SITE GridSite ;
 PIN p
  DIRECTION INPUT ;
  USE SIGNAL ;
  PORT
   LAYER M1 ;
   RECT 0.215000 0.140000 0.235000 0.160000 ;
  END
 END p
END physical_in15
MACRO physical_in16
 CLASS CORE ;
 ORIGIN 0 0 ;
 SIZE 0.450000 BY 0.300000 ;
 SYMMETRY X Y ;
 SITE GridSite ;
 PIN p
  DIRECTION INPUT ;
  USE SIGNAL ;
  PORT
   LAYER M1 ;
   RECT 0.215000 0.140000 0.235000 0.160000 ;
  END
 END p
END physical_in16
MACRO physical_in17
 CLASS CORE ;
 ORIGIN 0 0 ;
 SIZE 0.450000 BY 0.300000 ;
 SYMMETRY X Y ;
 SITE GridSite ;
 PIN p
  DIRECTION INPUT ;
  USE SIGNAL ;
  PORT
   LAYER M1 ;
   RECT 0.215000 0.140000 0.235000 0.160000 ;
  END
 END p
END physical_in17
MACRO physical_in18
 CLASS CORE ;
 ORIGIN 0 0 ;
 SIZE 0.450000 BY 0.300000 ;
 SYMMETRY X Y ;
 SITE GridSite ;
 PIN p
  DIRECTION INPUT ;
  USE SIGNAL ;
  PORT
   LAYER M1 ;
   RECT 0.215000 0.140000 0.235000 0.160000 ;
  END
 END p
END physical_in18
MACRO physical_in19
 CLASS CORE ;
 ORIGIN 0 0 ;
 SIZE 0.450000 BY 0.300000 ;
 SYMMETRY X Y ;
 SITE GridSite ;
 PIN p
  DIRECTION INPUT ;
  USE SIGNAL ;
  PORT
   LAYER M1 ;
   RECT 0.215000 0.140000 0.235000 0.160000 ;
  END
 END p
END physical_in19
MACRO physical_in20
 CLASS CORE ;
 ORIGIN 0 0 ;
 SIZE 0.450000 BY 0.300000 ;
 SYMMETRY X Y ;
 SITE GridSite ;
 PIN p
  DIRECTION INPUT ;
  USE SIGNAL ;
  PORT
   LAYER M1 ;
   RECT 0.215000 0.140000 0.235000 0.160000 ;
  END
 END p
END physical_in20
MACRO physical_in21
 CLASS CORE ;
 ORIGIN 0 0 ;
 SIZE 0.450000 BY 0.300000 ;
 SYMMETRY X Y ;
 SITE GridSite ;
 PIN p
  DIRECTION INPUT ;
  USE SIGNAL ;
  PORT
   LAYER M1 ;
   RECT 0.215000 0.140000 0.235000 0.160000 ;
  END
 END p
END physical_in21
MACRO physical_in22
 CLASS CORE ;
 ORIGIN 0 0 ;
 SIZE 0.450000 BY 0.300000 ;
 SYMMETRY X Y ;
 SITE GridSite ;
 PIN p
  DIRECTION INPUT ;
  USE SIGNAL ;
  PORT
   LAYER M1 ;
   RECT 0.215000 0.140000 0.235000 0.160000 ;
  END
 END p
END physical_in22
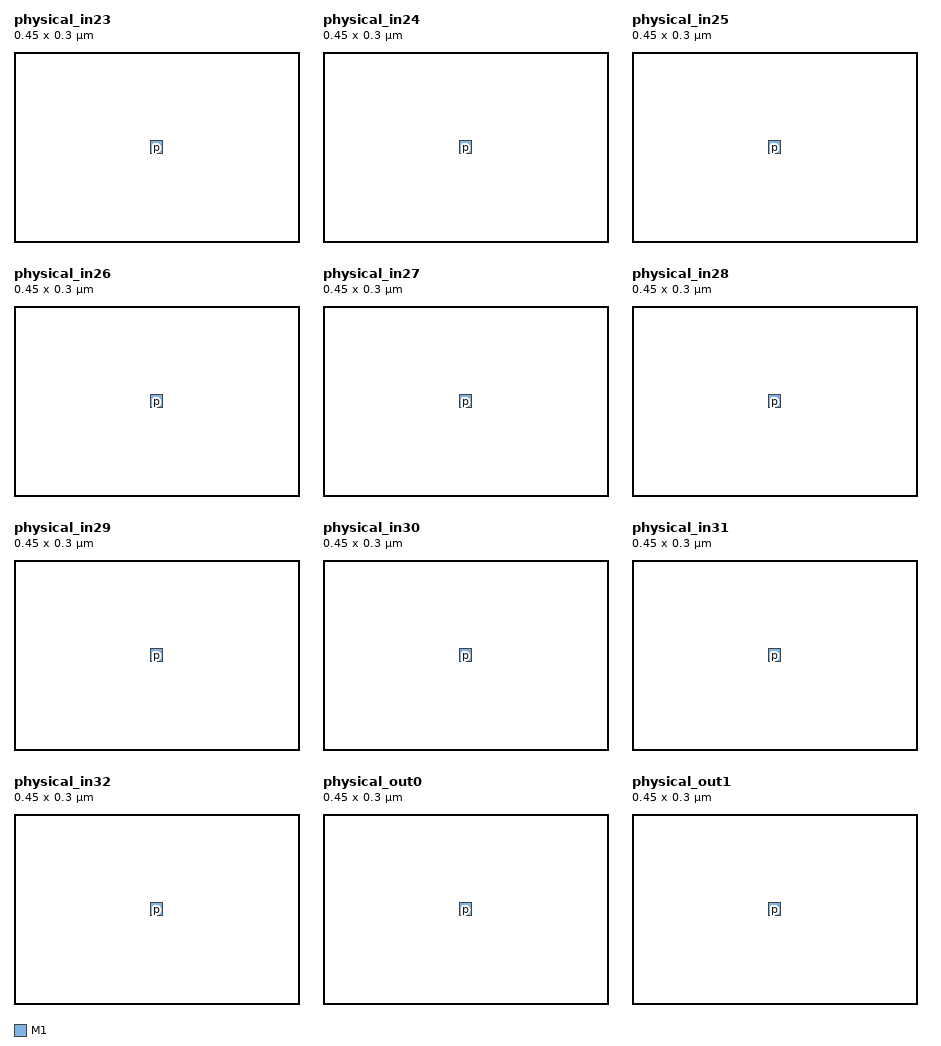
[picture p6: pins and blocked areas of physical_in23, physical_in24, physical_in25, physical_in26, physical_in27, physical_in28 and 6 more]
MACRO physical_in23
 CLASS CORE ;
 ORIGIN 0 0 ;
 SIZE 0.450000 BY 0.300000 ;
 SYMMETRY X Y ;
 SITE GridSite ;
 PIN p
  DIRECTION INPUT ;
  USE SIGNAL ;
  PORT
   LAYER M1 ;
   RECT 0.215000 0.140000 0.235000 0.160000 ;
  END
 END p
END physical_in23
MACRO physical_in24
 CLASS CORE ;
 ORIGIN 0 0 ;
 SIZE 0.450000 BY 0.300000 ;
 SYMMETRY X Y ;
 SITE GridSite ;
 PIN p
  DIRECTION INPUT ;
  USE SIGNAL ;
  PORT
   LAYER M1 ;
   RECT 0.215000 0.140000 0.235000 0.160000 ;
  END
 END p
END physical_in24
MACRO physical_in25
 CLASS CORE ;
 ORIGIN 0 0 ;
 SIZE 0.450000 BY 0.300000 ;
 SYMMETRY X Y ;
 SITE GridSite ;
 PIN p
  DIRECTION INPUT ;
  USE SIGNAL ;
  PORT
   LAYER M1 ;
   RECT 0.215000 0.140000 0.235000 0.160000 ;
  END
 END p
END physical_in25
MACRO physical_in26
 CLASS CORE ;
 ORIGIN 0 0 ;
 SIZE 0.450000 BY 0.300000 ;
 SYMMETRY X Y ;
 SITE GridSite ;
 PIN p
  DIRECTION INPUT ;
  USE SIGNAL ;
  PORT
   LAYER M1 ;
   RECT 0.215000 0.140000 0.235000 0.160000 ;
  END
 END p
END physical_in26
MACRO physical_in27
 CLASS CORE ;
 ORIGIN 0 0 ;
 SIZE 0.450000 BY 0.300000 ;
 SYMMETRY X Y ;
 SITE GridSite ;
 PIN p
  DIRECTION INPUT ;
  USE SIGNAL ;
  PORT
   LAYER M1 ;
   RECT 0.215000 0.140000 0.235000 0.160000 ;
  END
 END p
END physical_in27
MACRO physical_in28
 CLASS CORE ;
 ORIGIN 0 0 ;
 SIZE 0.450000 BY 0.300000 ;
 SYMMETRY X Y ;
 SITE GridSite ;
 PIN p
  DIRECTION INPUT ;
  USE SIGNAL ;
  PORT
   LAYER M1 ;
   RECT 0.215000 0.140000 0.235000 0.160000 ;
  END
 END p
END physical_in28
MACRO physical_in29
 CLASS CORE ;
 ORIGIN 0 0 ;
 SIZE 0.450000 BY 0.300000 ;
 SYMMETRY X Y ;
 SITE GridSite ;
 PIN p
  DIRECTION INPUT ;
  USE SIGNAL ;
  PORT
   LAYER M1 ;
   RECT 0.215000 0.140000 0.235000 0.160000 ;
  END
 END p
END physical_in29
MACRO physical_in30
 CLASS CORE ;
 ORIGIN 0 0 ;
 SIZE 0.450000 BY 0.300000 ;
 SYMMETRY X Y ;
 SITE GridSite ;
 PIN p
  DIRECTION INPUT ;
  USE SIGNAL ;
  PORT
   LAYER M1 ;
   RECT 0.215000 0.140000 0.235000 0.160000 ;
  END
 END p
END physical_in30
MACRO physical_in31
 CLASS CORE ;
 ORIGIN 0 0 ;
 SIZE 0.450000 BY 0.300000 ;
 SYMMETRY X Y ;
 SITE GridSite ;
 PIN p
  DIRECTION INPUT ;
  USE SIGNAL ;
  PORT
   LAYER M1 ;
   RECT 0.215000 0.140000 0.235000 0.160000 ;
  END
 END p
END physical_in31
MACRO physical_in32
 CLASS CORE ;
 ORIGIN 0 0 ;
 SIZE 0.450000 BY 0.300000 ;
 SYMMETRY X Y ;
 SITE GridSite ;
 PIN p
  DIRECTION INPUT ;
  USE SIGNAL ;
  PORT
   LAYER M1 ;
   RECT 0.215000 0.140000 0.235000 0.160000 ;
  END
 END p
END physical_in32
MACRO physical_out0
 CLASS CORE ;
 ORIGIN 0 0 ;
 SIZE 0.450000 BY 0.300000 ;
 SYMMETRY X Y ;
 SITE GridSite ;
 PIN p
  DIRECTION INPUT ;
  USE SIGNAL ;
  PORT
   LAYER M1 ;
   RECT 0.215000 0.140000 0.235000 0.160000 ;
  END
 END p
END physical_out0
MACRO physical_out1
 CLASS CORE ;
 ORIGIN 0 0 ;
 SIZE 0.450000 BY 0.300000 ;
 SYMMETRY X Y ;
 SITE GridSite ;
 PIN p
  DIRECTION INPUT ;
  USE SIGNAL ;
  PORT
   LAYER M1 ;
   RECT 0.215000 0.140000 0.235000 0.160000 ;
  END
 END p
END physical_out1
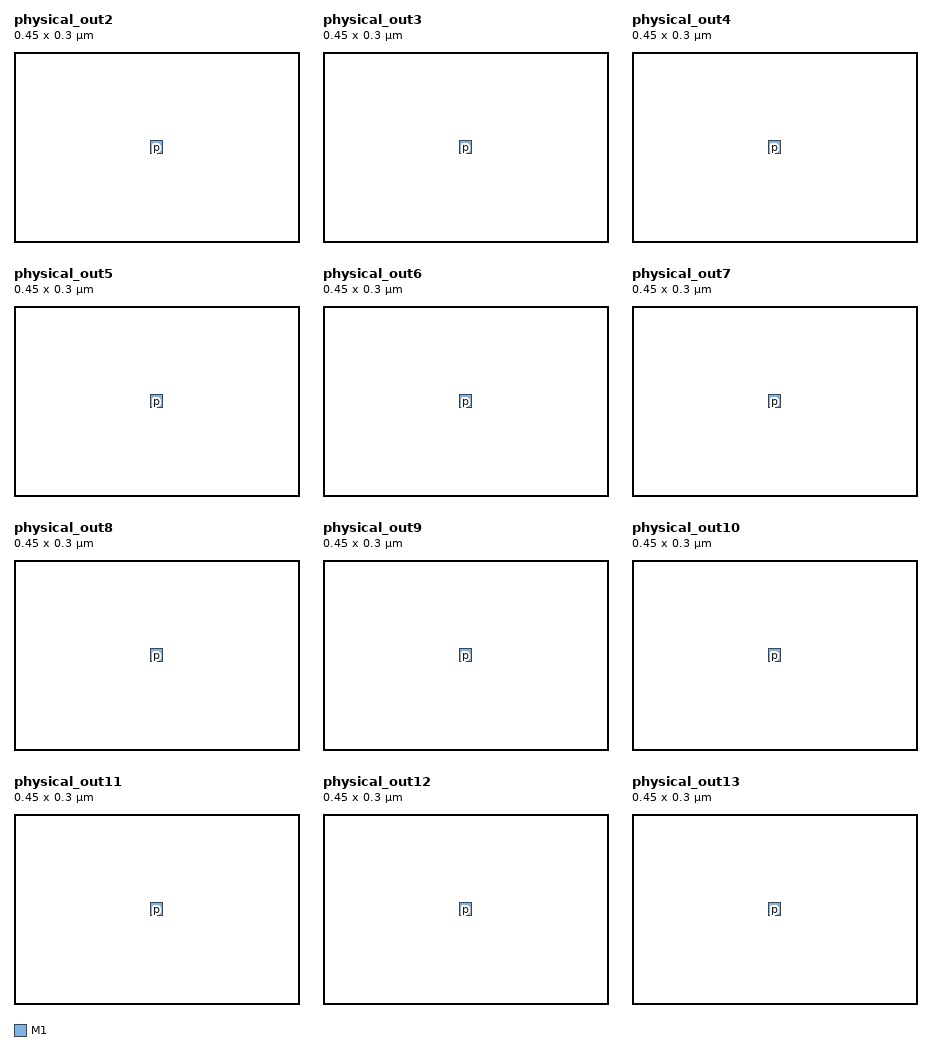
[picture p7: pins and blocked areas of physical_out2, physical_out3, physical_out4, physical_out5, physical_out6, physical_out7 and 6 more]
MACRO physical_out2
 CLASS CORE ;
 ORIGIN 0 0 ;
 SIZE 0.450000 BY 0.300000 ;
 SYMMETRY X Y ;
 SITE GridSite ;
 PIN p
  DIRECTION INPUT ;
  USE SIGNAL ;
  PORT
   LAYER M1 ;
   RECT 0.215000 0.140000 0.235000 0.160000 ;
  END
 END p
END physical_out2
MACRO physical_out3
 CLASS CORE ;
 ORIGIN 0 0 ;
 SIZE 0.450000 BY 0.300000 ;
 SYMMETRY X Y ;
 SITE GridSite ;
 PIN p
  DIRECTION INPUT ;
  USE SIGNAL ;
  PORT
   LAYER M1 ;
   RECT 0.215000 0.140000 0.235000 0.160000 ;
  END
 END p
END physical_out3
MACRO physical_out4
 CLASS CORE ;
 ORIGIN 0 0 ;
 SIZE 0.450000 BY 0.300000 ;
 SYMMETRY X Y ;
 SITE GridSite ;
 PIN p
  DIRECTION INPUT ;
  USE SIGNAL ;
  PORT
   LAYER M1 ;
   RECT 0.215000 0.140000 0.235000 0.160000 ;
  END
 END p
END physical_out4
MACRO physical_out5
 CLASS CORE ;
 ORIGIN 0 0 ;
 SIZE 0.450000 BY 0.300000 ;
 SYMMETRY X Y ;
 SITE GridSite ;
 PIN p
  DIRECTION INPUT ;
  USE SIGNAL ;
  PORT
   LAYER M1 ;
   RECT 0.215000 0.140000 0.235000 0.160000 ;
  END
 END p
END physical_out5
MACRO physical_out6
 CLASS CORE ;
 ORIGIN 0 0 ;
 SIZE 0.450000 BY 0.300000 ;
 SYMMETRY X Y ;
 SITE GridSite ;
 PIN p
  DIRECTION INPUT ;
  USE SIGNAL ;
  PORT
   LAYER M1 ;
   RECT 0.215000 0.140000 0.235000 0.160000 ;
  END
 END p
END physical_out6
MACRO physical_out7
 CLASS CORE ;
 ORIGIN 0 0 ;
 SIZE 0.450000 BY 0.300000 ;
 SYMMETRY X Y ;
 SITE GridSite ;
 PIN p
  DIRECTION INPUT ;
  USE SIGNAL ;
  PORT
   LAYER M1 ;
   RECT 0.215000 0.140000 0.235000 0.160000 ;
  END
 END p
END physical_out7
MACRO physical_out8
 CLASS CORE ;
 ORIGIN 0 0 ;
 SIZE 0.450000 BY 0.300000 ;
 SYMMETRY X Y ;
 SITE GridSite ;
 PIN p
  DIRECTION INPUT ;
  USE SIGNAL ;
  PORT
   LAYER M1 ;
   RECT 0.215000 0.140000 0.235000 0.160000 ;
  END
 END p
END physical_out8
MACRO physical_out9
 CLASS CORE ;
 ORIGIN 0 0 ;
 SIZE 0.450000 BY 0.300000 ;
 SYMMETRY X Y ;
 SITE GridSite ;
 PIN p
  DIRECTION INPUT ;
  USE SIGNAL ;
  PORT
   LAYER M1 ;
   RECT 0.215000 0.140000 0.235000 0.160000 ;
  END
 END p
END physical_out9
MACRO physical_out10
 CLASS CORE ;
 ORIGIN 0 0 ;
 SIZE 0.450000 BY 0.300000 ;
 SYMMETRY X Y ;
 SITE GridSite ;
 PIN p
  DIRECTION INPUT ;
  USE SIGNAL ;
  PORT
   LAYER M1 ;
   RECT 0.215000 0.140000 0.235000 0.160000 ;
  END
 END p
END physical_out10
MACRO physical_out11
 CLASS CORE ;
 ORIGIN 0 0 ;
 SIZE 0.450000 BY 0.300000 ;
 SYMMETRY X Y ;
 SITE GridSite ;
 PIN p
  DIRECTION INPUT ;
  USE SIGNAL ;
  PORT
   LAYER M1 ;
   RECT 0.215000 0.140000 0.235000 0.160000 ;
  END
 END p
END physical_out11
MACRO physical_out12
 CLASS CORE ;
 ORIGIN 0 0 ;
 SIZE 0.450000 BY 0.300000 ;
 SYMMETRY X Y ;
 SITE GridSite ;
 PIN p
  DIRECTION INPUT ;
  USE SIGNAL ;
  PORT
   LAYER M1 ;
   RECT 0.215000 0.140000 0.235000 0.160000 ;
  END
 END p
END physical_out12
MACRO physical_out13
 CLASS CORE ;
 ORIGIN 0 0 ;
 SIZE 0.450000 BY 0.300000 ;
 SYMMETRY X Y ;
 SITE GridSite ;
 PIN p
  DIRECTION INPUT ;
  USE SIGNAL ;
  PORT
   LAYER M1 ;
   RECT 0.215000 0.140000 0.235000 0.160000 ;
  END
 END p
END physical_out13
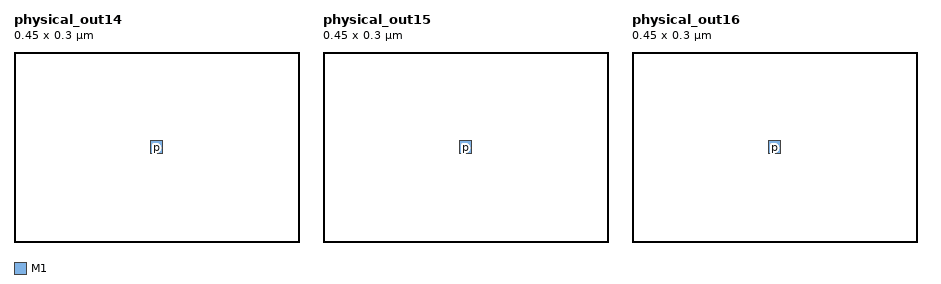
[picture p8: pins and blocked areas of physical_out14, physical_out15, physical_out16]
MACRO physical_out14
 CLASS CORE ;
 ORIGIN 0 0 ;
 SIZE 0.450000 BY 0.300000 ;
 SYMMETRY X Y ;
 SITE GridSite ;
 PIN p
  DIRECTION INPUT ;
  USE SIGNAL ;
  PORT
   LAYER M1 ;
   RECT 0.215000 0.140000 0.235000 0.160000 ;
  END
 END p
END physical_out14
MACRO physical_out15
 CLASS CORE ;
 ORIGIN 0 0 ;
 SIZE 0.450000 BY 0.300000 ;
 SYMMETRY X Y ;
 SITE GridSite ;
 PIN p
  DIRECTION INPUT ;
  USE SIGNAL ;
  PORT
   LAYER M1 ;
   RECT 0.215000 0.140000 0.235000 0.160000 ;
  END
 END p
END physical_out15
MACRO physical_out16
 CLASS CORE ;
 ORIGIN 0 0 ;
 SIZE 0.450000 BY 0.300000 ;
 SYMMETRY X Y ;
 SITE GridSite ;
 PIN p
  DIRECTION INPUT ;
  USE SIGNAL ;
  PORT
   LAYER M1 ;
   RECT 0.215000 0.140000 0.235000 0.160000 ;
  END
 END p
END physical_out16
END LIBRARY
